VERSION 5.8 ;
BUSBITCHARS "[]" ;
DIVIDERCHAR "/" ;
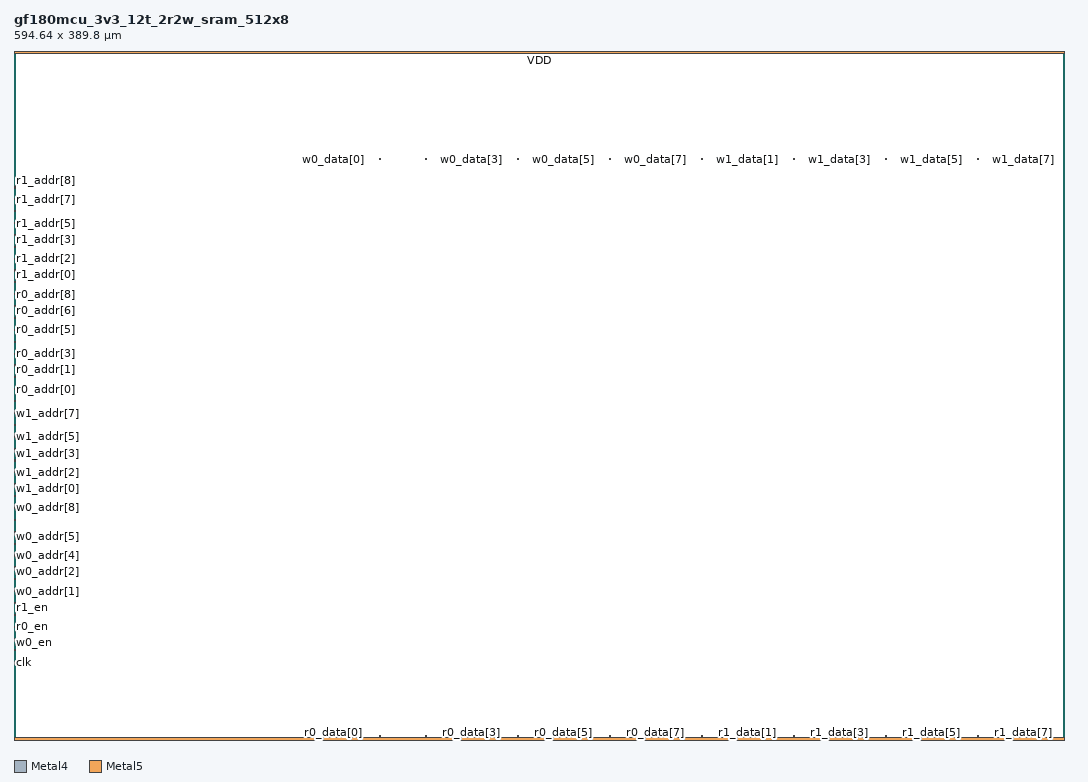
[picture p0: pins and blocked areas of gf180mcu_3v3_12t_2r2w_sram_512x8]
MACRO gf180mcu_3v3_12t_2r2w_sram_512x8
  CLASS BLOCK ;
  FOREIGN gf180mcu_3v3_12t_2r2w_sram_512x8 0.000 0.000 ;
  ORIGIN 0.000 0.000 ;
  SIZE 594.640000 BY 389.800000 ;
  SYMMETRY X Y ;
  PIN clk
    DIRECTION INPUT ;
    USE SIGNAL ;
    PORT
      LAYER Metal4 ;
        RECT 0.320000 43.680000 0.960000 44.320000 ;
    END
  END clk
  PIN w0_en
    DIRECTION INPUT ;
    USE SIGNAL ;
    PORT
      LAYER Metal4 ;
        RECT 0.320000 50.405000 0.960000 51.045000 ;
    END
  END w0_en
  PIN w1_en
    DIRECTION INPUT ;
    USE SIGNAL ;
    PORT
      LAYER Metal4 ;
        RECT 0.320000 57.125000 0.960000 57.765000 ;
    END
  END w1_en
  PIN r0_en
    DIRECTION INPUT ;
    USE SIGNAL ;
    PORT
      LAYER Metal4 ;
        RECT 0.320000 63.850000 0.960000 64.490000 ;
    END
  END r0_en
  PIN r1_en
    DIRECTION INPUT ;
    USE SIGNAL ;
    PORT
      LAYER Metal4 ;
        RECT 0.320000 70.575000 0.960000 71.215000 ;
    END
  END r1_en
  PIN w0_addr[0]
    DIRECTION INPUT ;
    USE SIGNAL ;
    PORT
      LAYER Metal4 ;
        RECT 0.320000 77.295000 0.960000 77.935000 ;
    END
  END w0_addr[0]
  PIN w0_addr[1]
    DIRECTION INPUT ;
    USE SIGNAL ;
    PORT
      LAYER Metal4 ;
        RECT 0.320000 84.020000 0.960000 84.660000 ;
    END
  END w0_addr[1]
  PIN w0_addr[2]
    DIRECTION INPUT ;
    USE SIGNAL ;
    PORT
      LAYER Metal4 ;
        RECT 0.320000 90.740000 0.960000 91.380000 ;
    END
  END w0_addr[2]
  PIN w0_addr[3]
    DIRECTION INPUT ;
    USE SIGNAL ;
    PORT
      LAYER Metal4 ;
        RECT 0.320000 97.465000 0.960000 98.105000 ;
    END
  END w0_addr[3]
  PIN w0_addr[4]
    DIRECTION INPUT ;
    USE SIGNAL ;
    PORT
      LAYER Metal4 ;
        RECT 0.320000 104.190000 0.960000 104.830000 ;
    END
  END w0_addr[4]
  PIN w0_addr[5]
    DIRECTION INPUT ;
    USE SIGNAL ;
    PORT
      LAYER Metal4 ;
        RECT 0.320000 110.910000 0.960000 111.550000 ;
    END
  END w0_addr[5]
  PIN w0_addr[6]
    DIRECTION INPUT ;
    USE SIGNAL ;
    PORT
      LAYER Metal4 ;
        RECT 0.320000 117.635000 0.960000 118.275000 ;
    END
  END w0_addr[6]
  PIN w0_addr[7]
    DIRECTION INPUT ;
    USE SIGNAL ;
    PORT
      LAYER Metal4 ;
        RECT 0.320000 124.355000 0.960000 124.995000 ;
    END
  END w0_addr[7]
  PIN w0_addr[8]
    DIRECTION INPUT ;
    USE SIGNAL ;
    PORT
      LAYER Metal4 ;
        RECT 0.320000 131.080000 0.960000 131.720000 ;
    END
  END w0_addr[8]
  PIN w1_addr[0]
    DIRECTION INPUT ;
    USE SIGNAL ;
    PORT
      LAYER Metal4 ;
        RECT 0.320000 137.800000 0.960000 138.440000 ;
    END
  END w1_addr[0]
  PIN w1_addr[1]
    DIRECTION INPUT ;
    USE SIGNAL ;
    PORT
      LAYER Metal4 ;
        RECT 0.320000 144.525000 0.960000 145.165000 ;
    END
  END w1_addr[1]
  PIN w1_addr[2]
    DIRECTION INPUT ;
    USE SIGNAL ;
    PORT
      LAYER Metal4 ;
        RECT 0.320000 151.250000 0.960000 151.890000 ;
    END
  END w1_addr[2]
  PIN w1_addr[3]
    DIRECTION INPUT ;
    USE SIGNAL ;
    PORT
      LAYER Metal4 ;
        RECT 0.320000 157.970000 0.960000 158.610000 ;
    END
  END w1_addr[3]
  PIN w1_addr[4]
    DIRECTION INPUT ;
    USE SIGNAL ;
    PORT
      LAYER Metal4 ;
        RECT 0.320000 164.695000 0.960000 165.335000 ;
    END
  END w1_addr[4]
  PIN w1_addr[5]
    DIRECTION INPUT ;
    USE SIGNAL ;
    PORT
      LAYER Metal4 ;
        RECT 0.320000 171.415000 0.960000 172.055000 ;
    END
  END w1_addr[5]
  PIN w1_addr[6]
    DIRECTION INPUT ;
    USE SIGNAL ;
    PORT
      LAYER Metal4 ;
        RECT 0.320000 178.140000 0.960000 178.780000 ;
    END
  END w1_addr[6]
  PIN w1_addr[7]
    DIRECTION INPUT ;
    USE SIGNAL ;
    PORT
      LAYER Metal4 ;
        RECT 0.320000 184.865000 0.960000 185.505000 ;
    END
  END w1_addr[7]
  PIN w1_addr[8]
    DIRECTION INPUT ;
    USE SIGNAL ;
    PORT
      LAYER Metal4 ;
        RECT 0.320000 191.585000 0.960000 192.225000 ;
    END
  END w1_addr[8]
  PIN r0_addr[0]
    DIRECTION INPUT ;
    USE SIGNAL ;
    PORT
      LAYER Metal4 ;
        RECT 0.320000 198.310000 0.960000 198.950000 ;
    END
  END r0_addr[0]
  PIN r0_addr[1]
    DIRECTION INPUT ;
    USE SIGNAL ;
    PORT
      LAYER Metal4 ;
        RECT 0.320000 205.030000 0.960000 205.670000 ;
    END
  END r0_addr[1]
  PIN r0_addr[2]
    DIRECTION INPUT ;
    USE SIGNAL ;
    PORT
      LAYER Metal4 ;
        RECT 0.320000 211.755000 0.960000 212.395000 ;
    END
  END r0_addr[2]
  PIN r0_addr[3]
    DIRECTION INPUT ;
    USE SIGNAL ;
    PORT
      LAYER Metal4 ;
        RECT 0.320000 218.480000 0.960000 219.120000 ;
    END
  END r0_addr[3]
  PIN r0_addr[4]
    DIRECTION INPUT ;
    USE SIGNAL ;
    PORT
      LAYER Metal4 ;
        RECT 0.320000 225.200000 0.960000 225.840000 ;
    END
  END r0_addr[4]
  PIN r0_addr[5]
    DIRECTION INPUT ;
    USE SIGNAL ;
    PORT
      LAYER Metal4 ;
        RECT 0.320000 231.925000 0.960000 232.565000 ;
    END
  END r0_addr[5]
  PIN r0_addr[6]
    DIRECTION INPUT ;
    USE SIGNAL ;
    PORT
      LAYER Metal4 ;
        RECT 0.320000 238.645000 0.960000 239.285000 ;
    END
  END r0_addr[6]
  PIN r0_addr[7]
    DIRECTION INPUT ;
    USE SIGNAL ;
    PORT
      LAYER Metal4 ;
        RECT 0.320000 245.370000 0.960000 246.010000 ;
    END
  END r0_addr[7]
  PIN r0_addr[8]
    DIRECTION INPUT ;
    USE SIGNAL ;
    PORT
      LAYER Metal4 ;
        RECT 0.320000 252.090000 0.960000 252.730000 ;
    END
  END r0_addr[8]
  PIN r1_addr[0]
    DIRECTION INPUT ;
    USE SIGNAL ;
    PORT
      LAYER Metal4 ;
        RECT 0.320000 258.815000 0.960000 259.455000 ;
    END
  END r1_addr[0]
  PIN r1_addr[1]
    DIRECTION INPUT ;
    USE SIGNAL ;
    PORT
      LAYER Metal4 ;
        RECT 0.320000 265.540000 0.960000 266.180000 ;
    END
  END r1_addr[1]
  PIN r1_addr[2]
    DIRECTION INPUT ;
    USE SIGNAL ;
    PORT
      LAYER Metal4 ;
        RECT 0.320000 272.260000 0.960000 272.900000 ;
    END
  END r1_addr[2]
  PIN r1_addr[3]
    DIRECTION INPUT ;
    USE SIGNAL ;
    PORT
      LAYER Metal4 ;
        RECT 0.320000 278.985000 0.960000 279.625000 ;
    END
  END r1_addr[3]
  PIN r1_addr[4]
    DIRECTION INPUT ;
    USE SIGNAL ;
    PORT
      LAYER Metal4 ;
        RECT 0.320000 285.705000 0.960000 286.345000 ;
    END
  END r1_addr[4]
  PIN r1_addr[5]
    DIRECTION INPUT ;
    USE SIGNAL ;
    PORT
      LAYER Metal4 ;
        RECT 0.320000 292.430000 0.960000 293.070000 ;
    END
  END r1_addr[5]
  PIN r1_addr[6]
    DIRECTION INPUT ;
    USE SIGNAL ;
    PORT
      LAYER Metal4 ;
        RECT 0.320000 299.155000 0.960000 299.795000 ;
    END
  END r1_addr[6]
  PIN r1_addr[7]
    DIRECTION INPUT ;
    USE SIGNAL ;
    PORT
      LAYER Metal4 ;
        RECT 0.320000 305.875000 0.960000 306.515000 ;
    END
  END r1_addr[7]
  PIN r1_addr[8]
    DIRECTION INPUT ;
    USE SIGNAL ;
    PORT
      LAYER Metal4 ;
        RECT 0.320000 312.600000 0.960000 313.240000 ;
    END
  END r1_addr[8]
  PIN w0_data[0]
    DIRECTION INPUT ;
    USE SIGNAL ;
    PORT
      LAYER Metal5 ;
        RECT 180.710000 328.600000 181.350000 329.240000 ;
    END
  END w0_data[0]
  PIN w0_data[1]
    DIRECTION INPUT ;
    USE SIGNAL ;
    PORT
      LAYER Metal5 ;
        RECT 206.765000 328.600000 207.405000 329.240000 ;
    END
  END w0_data[1]
  PIN w0_data[2]
    DIRECTION INPUT ;
    USE SIGNAL ;
    PORT
      LAYER Metal5 ;
        RECT 232.825000 328.600000 233.465000 329.240000 ;
    END
  END w0_data[2]
  PIN w0_data[3]
    DIRECTION INPUT ;
    USE SIGNAL ;
    PORT
      LAYER Metal5 ;
        RECT 258.880000 328.600000 259.520000 329.240000 ;
    END
  END w0_data[3]
  PIN w0_data[4]
    DIRECTION INPUT ;
    USE SIGNAL ;
    PORT
      LAYER Metal5 ;
        RECT 284.940000 328.600000 285.580000 329.240000 ;
    END
  END w0_data[4]
  PIN w0_data[5]
    DIRECTION INPUT ;
    USE SIGNAL ;
    PORT
      LAYER Metal5 ;
        RECT 310.995000 328.600000 311.635000 329.240000 ;
    END
  END w0_data[5]
  PIN w0_data[6]
    DIRECTION INPUT ;
    USE SIGNAL ;
    PORT
      LAYER Metal5 ;
        RECT 337.055000 328.600000 337.695000 329.240000 ;
    END
  END w0_data[6]
  PIN w0_data[7]
    DIRECTION INPUT ;
    USE SIGNAL ;
    PORT
      LAYER Metal5 ;
        RECT 363.110000 328.600000 363.750000 329.240000 ;
    END
  END w0_data[7]
  PIN w1_data[0]
    DIRECTION INPUT ;
    USE SIGNAL ;
    PORT
      LAYER Metal5 ;
        RECT 389.170000 328.600000 389.810000 329.240000 ;
    END
  END w1_data[0]
  PIN w1_data[1]
    DIRECTION INPUT ;
    USE SIGNAL ;
    PORT
      LAYER Metal5 ;
        RECT 415.225000 328.600000 415.865000 329.240000 ;
    END
  END w1_data[1]
  PIN w1_data[2]
    DIRECTION INPUT ;
    USE SIGNAL ;
    PORT
      LAYER Metal5 ;
        RECT 441.285000 328.600000 441.925000 329.240000 ;
    END
  END w1_data[2]
  PIN w1_data[3]
    DIRECTION INPUT ;
    USE SIGNAL ;
    PORT
      LAYER Metal5 ;
        RECT 467.340000 328.600000 467.980000 329.240000 ;
    END
  END w1_data[3]
  PIN w1_data[4]
    DIRECTION INPUT ;
    USE SIGNAL ;
    PORT
      LAYER Metal5 ;
        RECT 493.400000 328.600000 494.040000 329.240000 ;
    END
  END w1_data[4]
  PIN w1_data[5]
    DIRECTION INPUT ;
    USE SIGNAL ;
    PORT
      LAYER Metal5 ;
        RECT 519.455000 328.600000 520.095000 329.240000 ;
    END
  END w1_data[5]
  PIN w1_data[6]
    DIRECTION INPUT ;
    USE SIGNAL ;
    PORT
      LAYER Metal5 ;
        RECT 545.515000 328.600000 546.155000 329.240000 ;
    END
  END w1_data[6]
  PIN w1_data[7]
    DIRECTION INPUT ;
    USE SIGNAL ;
    PORT
      LAYER Metal5 ;
        RECT 571.570000 328.600000 572.210000 329.240000 ;
    END
  END w1_data[7]
  PIN r0_data[0]
    DIRECTION OUTPUT ;
    USE SIGNAL ;
    PORT
      LAYER Metal5 ;
        RECT 180.710000 1.680000 181.350000 2.320000 ;
    END
  END r0_data[0]
  PIN r0_data[1]
    DIRECTION OUTPUT ;
    USE SIGNAL ;
    PORT
      LAYER Metal5 ;
        RECT 206.765000 1.680000 207.405000 2.320000 ;
    END
  END r0_data[1]
  PIN r0_data[2]
    DIRECTION OUTPUT ;
    USE SIGNAL ;
    PORT
      LAYER Metal5 ;
        RECT 232.825000 1.680000 233.465000 2.320000 ;
    END
  END r0_data[2]
  PIN r0_data[3]
    DIRECTION OUTPUT ;
    USE SIGNAL ;
    PORT
      LAYER Metal5 ;
        RECT 258.880000 1.680000 259.520000 2.320000 ;
    END
  END r0_data[3]
  PIN r0_data[4]
    DIRECTION OUTPUT ;
    USE SIGNAL ;
    PORT
      LAYER Metal5 ;
        RECT 284.940000 1.680000 285.580000 2.320000 ;
    END
  END r0_data[4]
  PIN r0_data[5]
    DIRECTION OUTPUT ;
    USE SIGNAL ;
    PORT
      LAYER Metal5 ;
        RECT 310.995000 1.680000 311.635000 2.320000 ;
    END
  END r0_data[5]
  PIN r0_data[6]
    DIRECTION OUTPUT ;
    USE SIGNAL ;
    PORT
      LAYER Metal5 ;
        RECT 337.055000 1.680000 337.695000 2.320000 ;
    END
  END r0_data[6]
  PIN r0_data[7]
    DIRECTION OUTPUT ;
    USE SIGNAL ;
    PORT
      LAYER Metal5 ;
        RECT 363.110000 1.680000 363.750000 2.320000 ;
    END
  END r0_data[7]
  PIN r1_data[0]
    DIRECTION OUTPUT ;
    USE SIGNAL ;
    PORT
      LAYER Metal5 ;
        RECT 389.170000 1.680000 389.810000 2.320000 ;
    END
  END r1_data[0]
  PIN r1_data[1]
    DIRECTION OUTPUT ;
    USE SIGNAL ;
    PORT
      LAYER Metal5 ;
        RECT 415.225000 1.680000 415.865000 2.320000 ;
    END
  END r1_data[1]
  PIN r1_data[2]
    DIRECTION OUTPUT ;
    USE SIGNAL ;
    PORT
      LAYER Metal5 ;
        RECT 441.285000 1.680000 441.925000 2.320000 ;
    END
  END r1_data[2]
  PIN r1_data[3]
    DIRECTION OUTPUT ;
    USE SIGNAL ;
    PORT
      LAYER Metal5 ;
        RECT 467.340000 1.680000 467.980000 2.320000 ;
    END
  END r1_data[3]
  PIN r1_data[4]
    DIRECTION OUTPUT ;
    USE SIGNAL ;
    PORT
      LAYER Metal5 ;
        RECT 493.400000 1.680000 494.040000 2.320000 ;
    END
  END r1_data[4]
  PIN r1_data[5]
    DIRECTION OUTPUT ;
    USE SIGNAL ;
    PORT
      LAYER Metal5 ;
        RECT 519.455000 1.680000 520.095000 2.320000 ;
    END
  END r1_data[5]
  PIN r1_data[6]
    DIRECTION OUTPUT ;
    USE SIGNAL ;
    PORT
      LAYER Metal5 ;
        RECT 545.515000 1.680000 546.155000 2.320000 ;
    END
  END r1_data[6]
  PIN r1_data[7]
    DIRECTION OUTPUT ;
    USE SIGNAL ;
    PORT
      LAYER Metal5 ;
        RECT 571.570000 1.680000 572.210000 2.320000 ;
    END
  END r1_data[7]
  PIN VDD
    DIRECTION INOUT ;
    USE POWER ;
    PORT
      LAYER Metal5 ;
        RECT 0.000000 388.600000 594.640000 389.800000 ;
    END
  END VDD
  PIN VSS
    DIRECTION INOUT ;
    USE GROUND ;
    PORT
      LAYER Metal5 ;
        RECT 0.000000 0.000000 594.640000 1.200000 ;
    END
  END VSS
END gf180mcu_3v3_12t_2r2w_sram_512x8
END LIBRARY
